VERSION 5.7 ;
  NOWIREEXTENSIONATPIN ON ;
  DIVIDERCHAR "/" ;
  BUSBITCHARS "[]" ;
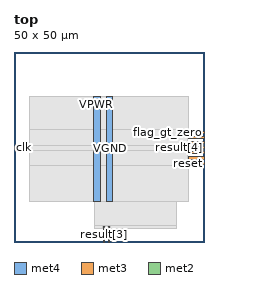
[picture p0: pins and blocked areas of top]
MACRO top
  CLASS BLOCK ;
  FOREIGN top ;
  ORIGIN 0.000 0.000 ;
  SIZE 50.000 BY 50.000 ;
  PIN VGND
    DIRECTION INOUT ;
    USE GROUND ;
    PORT
      LAYER met4 ;
        RECT 24.340 10.640 25.940 38.320 ;
    END
  END VGND
  PIN VPWR
    DIRECTION INOUT ;
    USE POWER ;
    PORT
      LAYER met4 ;
        RECT 21.040 10.640 22.640 38.320 ;
    END
  END VPWR
  PIN clk
    DIRECTION INPUT ;
    USE SIGNAL ;
    ANTENNAGATEAREA 0.852000 ;
    PORT
      LAYER met3 ;
        RECT 0.000 24.520 4.000 25.120 ;
    END
  END clk
  PIN flag_gt_zero
    DIRECTION OUTPUT ;
    USE SIGNAL ;
    PORT
      LAYER met3 ;
        RECT 46.000 28.600 50.000 29.200 ;
    END
  END flag_gt_zero
  PIN reset
    DIRECTION INPUT ;
    USE SIGNAL ;
    ANTENNAGATEAREA 0.196500 ;
    PORT
      LAYER met3 ;
        RECT 46.000 20.440 50.000 21.040 ;
    END
  END reset
  PIN result[0]
    DIRECTION OUTPUT ;
    USE SIGNAL ;
    ANTENNADIFFAREA 0.445500 ;
    PORT
      LAYER met3 ;
        RECT 46.000 23.160 50.000 23.760 ;
    END
  END result[0]
  PIN result[1]
    DIRECTION OUTPUT ;
    USE SIGNAL ;
    ANTENNADIFFAREA 0.445500 ;
    PORT
      LAYER met3 ;
        RECT 46.000 21.800 50.000 22.400 ;
    END
  END result[1]
  PIN result[2]
    DIRECTION OUTPUT ;
    USE SIGNAL ;
    ANTENNADIFFAREA 0.445500 ;
    PORT
      LAYER met3 ;
        RECT 46.000 27.240 50.000 27.840 ;
    END
  END result[2]
  PIN result[3]
    DIRECTION OUTPUT ;
    USE SIGNAL ;
    PORT
      LAYER met2 ;
        RECT 23.550 0.000 23.830 4.000 ;
    END
  END result[3]
  PIN result[4]
    DIRECTION OUTPUT ;
    USE SIGNAL ;
    ANTENNADIFFAREA 0.445500 ;
    PORT
      LAYER met3 ;
        RECT 46.000 24.520 50.000 25.120 ;
    END
  END result[4]
  PIN result[5]
    DIRECTION OUTPUT ;
    USE SIGNAL ;
    ANTENNADIFFAREA 0.445500 ;
    PORT
      LAYER met2 ;
        RECT 24.930 0.000 25.210 4.000 ;
    END
  END result[5]
  PIN result[6]
    DIRECTION OUTPUT ;
    USE SIGNAL ;
    ANTENNADIFFAREA 0.445500 ;
    PORT
      LAYER met3 ;
        RECT 46.000 25.880 50.000 26.480 ;
    END
  END result[6]
  OBS
      LAYER nwell ;
        RECT 5.330 10.795 44.350 38.165 ;
      LAYER li1 ;
        RECT 5.520 10.795 44.160 38.165 ;
      LAYER met1 ;
        RECT 5.520 10.640 44.160 38.320 ;
      LAYER met2 ;
        RECT 21.070 4.280 42.690 38.265 ;
        RECT 21.070 3.670 23.270 4.280 ;
        RECT 24.110 3.670 24.650 4.280 ;
        RECT 25.490 3.670 42.690 4.280 ;
      LAYER met3 ;
        RECT 4.000 29.600 46.000 38.245 ;
        RECT 4.000 25.520 45.600 29.600 ;
        RECT 4.400 24.120 45.600 25.520 ;
        RECT 4.000 20.040 45.600 24.120 ;
        RECT 4.000 10.715 46.000 20.040 ;
  END
END top
END LIBRARY

